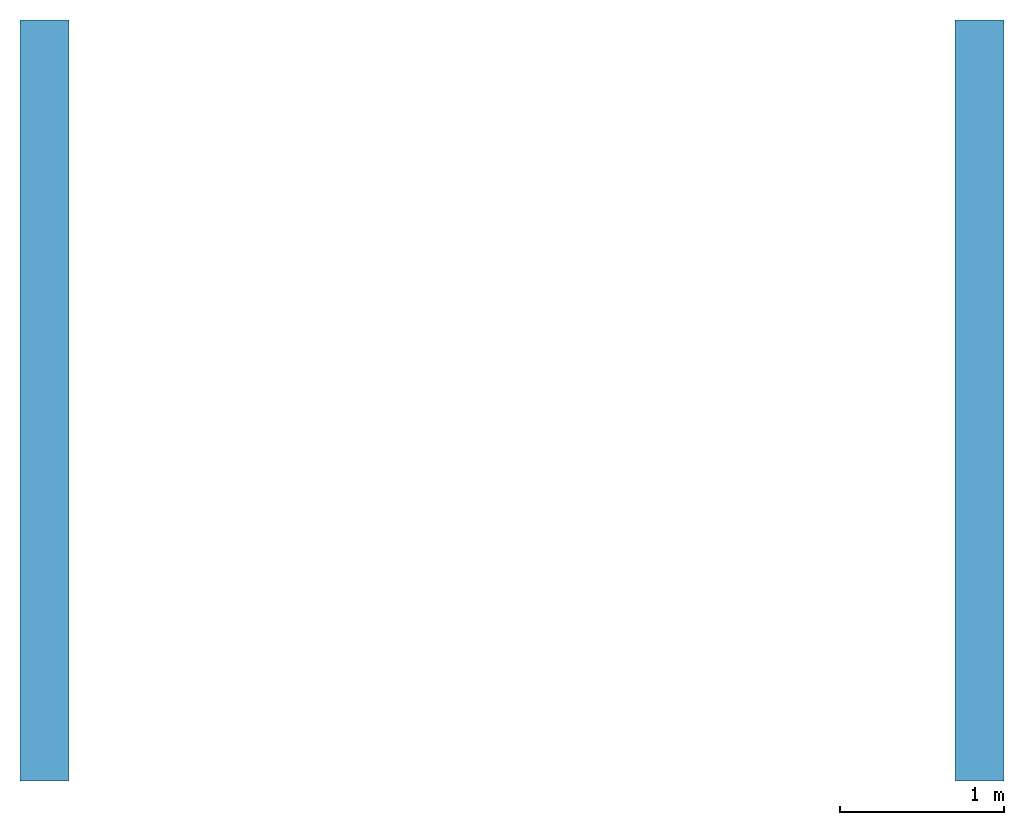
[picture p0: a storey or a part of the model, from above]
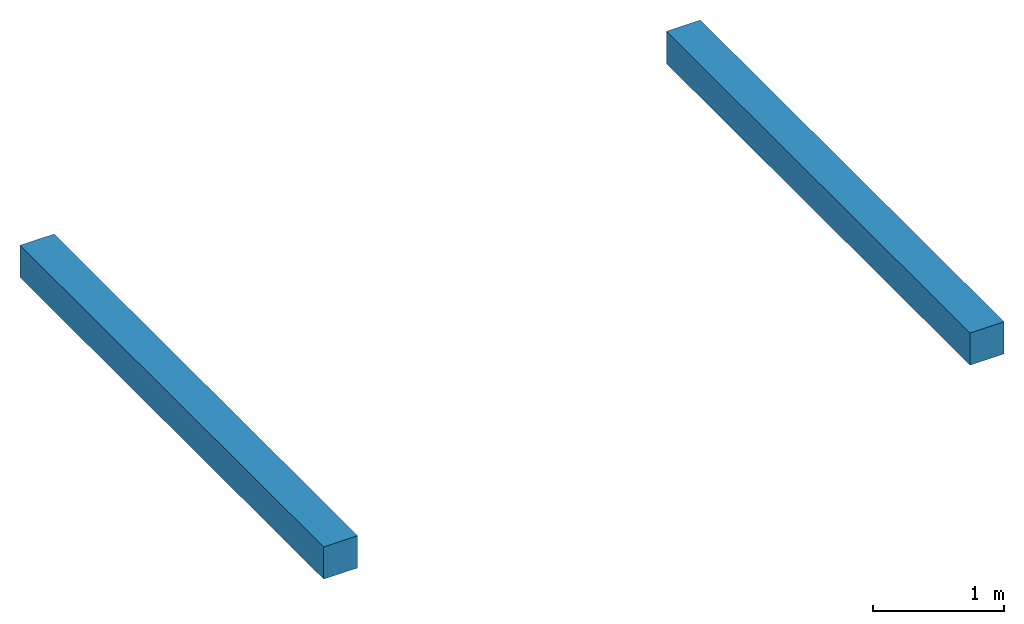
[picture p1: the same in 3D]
Properties of the parts of a building model (IFC2X3)

# File
Description: ViewDefinition [CoordinationView_V2.0, QuantityTakeOffAddOnView], ExchangeRequirement []
File name: 458-19
Time: 2019-10-06T19:30:17
Author: Igor MICHON
Organization: Lycée PIerre-Joël Bonté
Written by: The EXPRESS Data Manager Version 5.02.0100.07 : 28 Aug 2013
Made in: 20181011_1500(x64) - Exporter 18.4.0.0 - Interface alternative d'export 18.4.0.0
Comment: STEP Physical File produced by: The EXPRESS Data Manager Version 5.02.0100.07 : 28 Aug 2013 * Module: EDMstepFileFactory/EDMstandAlone * Creation date: Sun Oct 06 19:30:17 2019 * Host: DESKTOP-UCITT1H * Database: C:\Users\imich\AppData\Local\Temp\{CDE9F822-A233-403A-AE1A-1A95A778EC83}\ifc * Database version: 5507 * Database creation date: Sun Oct 06 19:30:13 2019 * Schema: IFC2X3 * Model: DataRepository.ifc * Model creation date: Sun Oct 06 19:30:14 2019 * Header model: DataRepository.ifc_HeaderModel * Header model creation date: Sun Oct 06 19:30:14 2019 * EDMuser: sdai-user * EDMgroup: sdai-group * License ID and type: 5605 : Permanent license. Expiry date: * EDMstepFileFactory options: 020000

# IfcProject, 458-19
LongName: Pont cadre fermé; Phase: DCE

# IfcSite, Default
RefLatitude: 48, 52, 0, 117187; RefLongitude: 2, 19, 59, 880409; RefElevation: 0 m

# IfcBuildingStorey: Niveau:Pointe 8 mm (2)
Name | LongName | Elevation (m)
Fondation Arase inférieur | Fondation Arase inférieur | 0
Traverse extrados | Traverse extrados | 3.6

# IfcBuildingElementProxy: Cadre, Cadre:Cadre:133698
In: Fondation Arase inférieur
Type - Material: Béton, C35/45 G+S
&Quantités de poutres et de contreventements - Elément de structure: Cadre: Cadre; Type: Cadre: Cadre
Avant-métré - Titre BPU: 600 Cadre; Numéro BPU: 604; Type: Cadre: Cadre

# IfcSlab: Sol:Béton de propreté (5)
In: Fondation Arase inférieur
Type - PredefinedType: FLOOR; Material: Béton, C20/25 0.1 m
Quantités de sols par assemblage - Assemblage de sol: Sol: Béton de propreté
Avant-métré - Type: Sol: Béton de propreté
BaseQuantities - Width: 0.1 m
Name (Sol:Béton de propreté:...) | Surface (définie par le modélisateur) (m2) = GrossArea (m2) | Titre BPU | Numéro BPU | NetArea (m2) | GrossVolume (m3) = NetVolume (m3) | Perimeter (m)
137328 | 8.65148 | 700 Murs en retour et murs en ailes | 701 | 18.6817 | 0.865148 | 13.7869
137388 | 29.76 | 600 Cadre | 601 | 61.72 | 2.976 | 22
137430 | 8.65148 | 700 Murs en retour et murs en ailes | 701 | 18.6817 | 0.865148 | 13.7869
137474 | 8.65148 | 700 Murs en retour et murs en ailes | 701 | 18.6817 | 0.865148 | 13.7869
137484 | 8.65148 | 700 Murs en retour et murs en ailes | 701 | 18.6817 | 0.865148 | 13.7869

# IfcWall: Joint sec (Cadre mur en retour) (4)
In: Fondation Arase inférieur
Type - Material: Mur par défaut
Quantités de murs par assemblage - Surface: 0.55425 m2; Volume: 0.032925 m3
Avant-métré - Titre BPU: 800 Joint
Name | Assemblage de mur = Type
Joint sec (Cadre mur en retour):Joint sec (Cadre mur en retour):136972 | Joint sec (Cadre mur en retour): Joint sec (Cadre mur en retour)
Joint sec (Cadre mur en retour)1:Joint sec (Cadre mur en retour):137050 | Joint sec (Cadre mur en retour)1: Joint sec (Cadre mur en retour)
Joint sec (Cadre mur en retour)2:Joint sec (Cadre mur en retour):137115 | Joint sec (Cadre mur en retour)2: Joint sec (Cadre mur en retour)
Joint sec (Cadre mur en retour)3:Joint sec (Cadre mur en retour):137138 | Joint sec (Cadre mur en retour)3: Joint sec (Cadre mur en retour)

# IfcWall: Mur en aile 1 (4)
In: Fondation Arase inférieur
Type - Material: Mur par défaut
Quantités de murs par assemblage - Surface: 17.35 m2; Volume: 12.1 m3
Avant-métré - Titre BPU: 700 Murs en retour et murs en ailes; Numéro BPU: 704
Name | Assemblage de mur = Type
Mur en aile 1:Mur en aile 1:135606 | Mur en aile 1: Mur en aile 1
Mur en aile 2:Mur en aile 1:135750 | Mur en aile 2: Mur en aile 1
Mur en aile 3:Mur en aile 1:135825 | Mur en aile 3: Mur en aile 1
Mur en aile 4:Mur en aile 1:135852 | Mur en aile 4: Mur en aile 1

# IfcWallStandardCase: Mur de base:Mur en retour (4)
In: Fondation Arase inférieur
Type - PredefinedType: STANDARD; Material: Béton, C35/45 G+S 0.3 m
Type - Quantités de murs par assemblage - Largeur: 0.3 m
BaseQuantities - Height: 3.9 m; Length: 1.83 m; Width: 0.3 m; GrossFootprintArea: 0.549 m2; NetVolume: 2.1411 m3; NetSideArea: 7.137 m2
Quantités de murs par assemblage - Assemblage de mur: Mur de base: Mur en retour; Longueur - Centre à centre: 1.83 m; Surface: 7.137 m2; Volume: 2.1411 m3
Avant-métré - Titre BPU: 700 Murs en retour et murs en ailes; Numéro BPU: 704; Type: Mur de base: Mur en retour
Name (Mur de base:Mur en retour:...)
134382
135724
135799
135826

# IfcWallStandardCase: Mur de base:Poutre de couronnement (2)
In: Traverse extrados
Type - PredefinedType: STANDARD; Material: Béton, C35/45 G+S 0.3 m
Type - Quantités de murs par assemblage - Largeur: 0.3 m
BaseQuantities - Height: 0.3 m; Length: 4.64 m; Width: 0.3 m; GrossFootprintArea: 1.392 m2; NetVolume: 0.4176 m3; NetSideArea: 1.392 m2
Quantités de murs par assemblage - Assemblage de mur: Mur de base: Poutre de couronnement; Longueur - Centre à centre: 4.64 m; Surface: 1.392 m2; Volume: 0.4176 m3
Avant-métré - Titre BPU: 600 Cadre; Numéro BPU: 604; Type: Mur de base: Poutre de couronnement
Name (Mur de base:Poutre de couronnement:...)
135927
136028
